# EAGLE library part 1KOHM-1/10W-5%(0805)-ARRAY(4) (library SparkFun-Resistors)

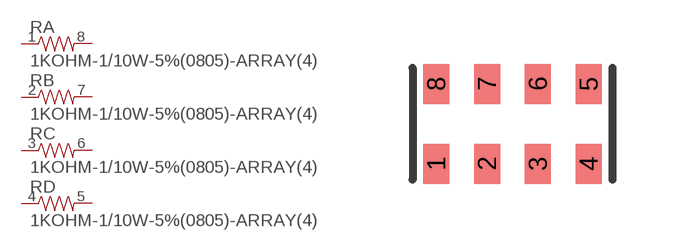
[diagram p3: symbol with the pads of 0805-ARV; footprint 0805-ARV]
Designator prefix R; gates A=RESISTOR-1 B=RESISTOR-1 C=RESISTOR-1 D=RESISTOR-1

## 1KOHM-1/10W-5%(0805)-ARRAY(4) (PROD_ID: RES-13020; VALUE: 1K)  [0805-ARV]
1  A:1  pas
2  B:1  pas
3  C:1  pas
4  D:1  pas
5  D:2  pas
6  C:2  pas
7  B:2  pas
8  A:2  pas

## Footprint 0805-ARV (pad centres in mm)
smd 0.65 x 1: 1 -1.905,-1; 2 -0.635,-1; 3 0.635,-1; 4 1.905,-1; 5 1.905,1; 6 0.635,1; 7 -0.635,1; 8 -1.905,1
